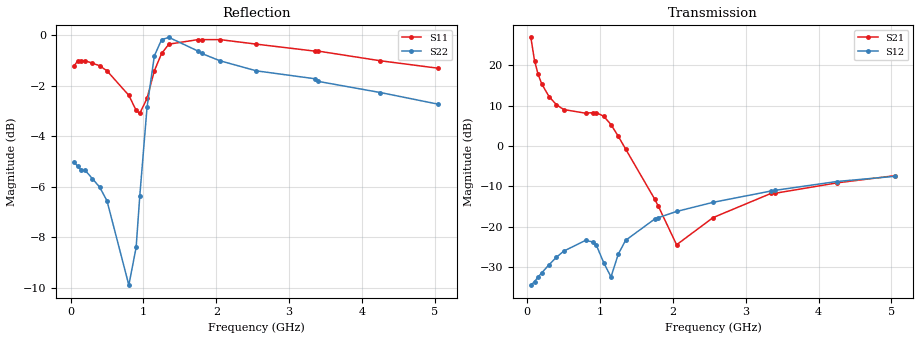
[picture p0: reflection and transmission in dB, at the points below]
!AT-33225
!S-PARAMETERS at Vce=3.6V  Ic=150mA.  LAST UPDATED 08-05-96
# ghz s ma r 50
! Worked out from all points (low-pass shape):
!   101 points, 50 MHz to 5.05 GHz, reference 50 ohm
!   highest |S21| = 26.89 dB at 50 MHz (marker M1); lowest = -24.4 dB at 2.05 GHz (marker M2)
!   |S21| within 3 dB of the highest: start of sweep to 76 MHz
!   lowest |S11| = -3.1 dB at 950 MHz (marker M3), VSWR 5.67, Z = 8.85 + j2.54 ohm
!   |S11| at or under -10 dB: nowhere
!   |S22| runs from -9.9 to -0.1 dB; largest |S21 - S12| = 22
!   S11 on the Smith chart (normalised r, x): 50 MHz: 0.07, -0.15; 500 MHz: 0.08, +0.07; 1.15 GHz: 0.08, -0.01; 1.8 GHz: 0.01, +0.16; 3.35 GHz: 0.04, +0.36; 5.05 GHz: 0.10, +0.60
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0.05  0.87 -163.0  22.11 100.0  0.019 25.0  0.56 -150.0
0.1  0.89 -173.0  11.38 91.0  0.021 30.0  0.55 -166.0
0.15  0.89 -177.0  7.69 86.0  0.024 36.0  0.54 -172.0
0.2  0.89 -179.0  5.85 82.0  0.027 41.0  0.54 -176.0
0.3  0.88 177.0  4.09 75.0  0.034 47.0  0.52 -180.0
0.4  0.87 175.0  3.25 69.0  0.042 49.0  0.5 178.0
0.5  0.85 172.0  2.83 61.0  0.05 49.0  0.47 177.0
0.8  0.76 169.0  2.55 31.0  0.068 35.0  0.32 -163.0
0.9  0.71 171.0  2.59 13.0  0.065 25.0  0.38 -140.0
0.95  0.7 174.0  2.58 2.0  0.059 20.0  0.48 -134.0
1.05  0.75 -180.0  2.34 -23.0  0.036 17.0  0.72 -137.0
1.15  0.85 -179.0  1.84 -47.0  0.024 68.0  0.91 -150.0
1.25  0.92 177.0  1.32 -67.0  0.046 93.0  0.98 -162.0
1.35  0.96 174.0  0.92 -81.0  0.068 92.0  0.99 -171.0
1.75  0.98 163.0  0.22 -119.0  0.125 78.0  0.93 171.0
1.8  0.98 162.0  0.18 -125.0  0.13 77.0  0.92 169.0
2.05  0.98 158.0  0.06 179.0  0.155 71.0  0.89 163.0
2.55  0.96 151.0  0.13 79.0  0.201 62.0  0.85 153.0
3.35  0.93 140.0  0.26 53.0  0.278 50.0  0.82 137.0
3.4  0.93 140.0  0.26 52.0  0.283 49.0  0.81 136.0
4.25  0.89 129.0  0.35 34.0  0.364 32.0  0.77 116.0
5.05  0.86 118.0  0.43 18.0  0.422 17.0  0.73 95.0
